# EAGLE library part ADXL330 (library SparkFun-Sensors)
Triple Axis Accelerometer Analog Devices ADXL330 +/-3g 2.4V-5.25V Analog output. Spark Fun Electronics SKU : COM-00730. Center pad paste layer has been reduced to avoid shorting.

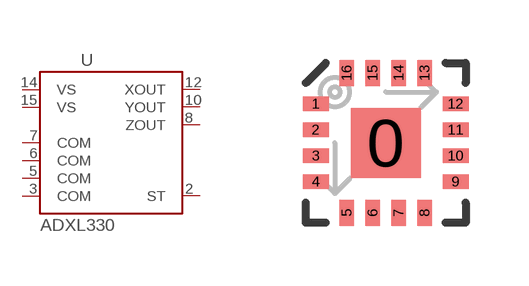
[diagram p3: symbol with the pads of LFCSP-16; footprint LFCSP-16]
Designator prefix -

## ADXL330SMD  [LFCSP-16]
2  ST
3  COM
5  COM
6  COM
7  COM
8  ZOUT
10  YOUT
12  XOUT
14  VS
15  VS

## Footprint LFCSP-16 (pad centres in mm)
smd 1.75 x 1.75: 0 0,0
smd 0.65 x 0.37: 1 -1.75,0.975; 2 -1.75,0.325; 3 -1.75,-0.325; 4 -1.75,-0.975; 9 1.75,-0.975; 10 1.75,-0.325; 11 1.75,0.325; 12 1.75,0.975
smd 0.37 x 0.65: 5 -0.975,-1.75; 6 -0.325,-1.75; 7 0.325,-1.75; 8 0.975,-1.75; 13 0.975,1.75; 14 0.325,1.75; 15 -0.325,1.75; 16 -0.975,1.75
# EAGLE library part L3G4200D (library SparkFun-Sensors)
L3G4200D Three-axis, digital output gyroscope The L3G4200D is a low-power three-axis angular rate sensor, has a full scale of ±250/±500/±2000 dps and is capable of measuring rates with a user-selectable bandwidth. It includes a sensing element and an IC interface capable of providing the measured angular rate to the external world through a digital interface (I2C/SPI). Package: 4x4x1.1 LGA-16 (LGA16-4x4.PAC)

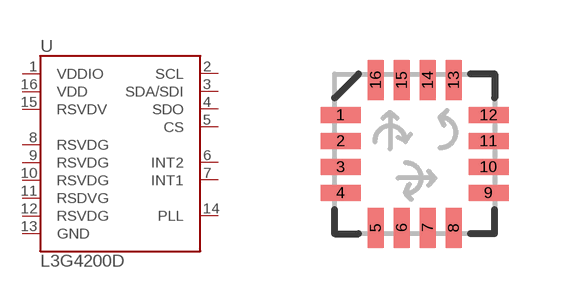
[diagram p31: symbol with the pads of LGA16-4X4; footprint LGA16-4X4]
Designator prefix U

## L3G4200D  [LGA16-4X4]
1  VDDIO
2  SCL
3  SDA/SDI
4  SDO
5  CS
6  INT2
7  INT1
8  RSVDG
9  RSVDG
10  RSVDG
11  RSDVG
12  RSVDG
13  GND
14  PLL
15  RSVDV
16  VDD

## Footprint LGA16-4X4 (pad centres in mm)
16-pin LGA Package 4x4x1.1mm 0.65mm pitch 4pins-by-4pins Package used by L3G4200D 3-axis gyro ***UNPROVEN***
smd 1 x 0.4: 1 -1.85,0.975; 2 -1.85,0.325; 3 -1.85,-0.325; 4 -1.85,-0.975; 9 1.85,-0.975; 10 1.85,-0.325; 11 1.85,0.325; 12 1.85,0.975
smd 0.4 x 1: 5 -0.975,-1.85; 6 -0.325,-1.85; 7 0.325,-1.85; 8 0.975,-1.85; 13 0.975,1.85; 14 0.325,1.85; 15 -0.325,1.85; 16 -0.975,1.85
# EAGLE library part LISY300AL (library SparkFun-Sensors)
Single-axis 300 deg/s analog gyroscope. Untested part.

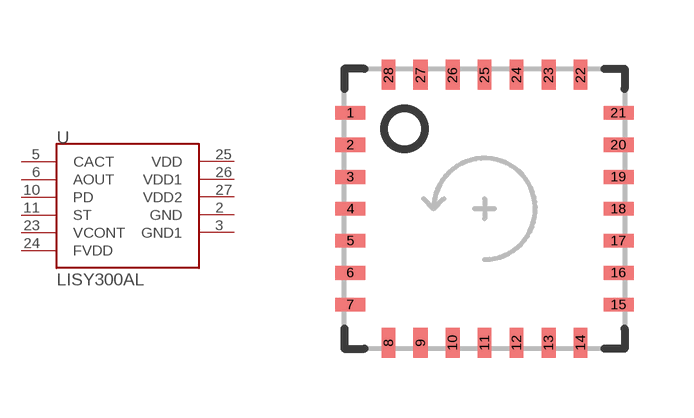
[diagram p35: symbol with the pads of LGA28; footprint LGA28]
Designator prefix -

## LISY300ALSMD  [LGA28]
2  GND
3  GND1
5  CACT
6  AOUT
10  PD
11  ST
23  VCONT
24  FVDD
25  VDD
26  VDD1
27  VDD2

## Footprint LGA28 (pad centres in mm)
Untested fp for LGA28 package
smd 0.75 x 0.35: 1 -3.35,2.4; 2 -3.35,1.6; 3 -3.35,0.8; 4 -3.35,0; 5 -3.35,-0.8; 6 -3.35,-1.6; 7 -3.35,-2.4; 15 3.35,-2.4; 16 3.35,-1.6; 17 3.35,-0.8; 18 3.35,0; 19 3.35,0.8; 20 3.35,1.6; 21 3.35,2.4
smd 0.35 x 0.75: 8 -2.4,-3.35; 9 -1.6,-3.35; 10 -0.8,-3.35; 11 0,-3.35; 12 0.8,-3.35; 13 1.6,-3.35; 14 2.4,-3.35; 22 2.4,3.35; 23 1.6,3.35; 24 0.8,3.35; 25 0,3.35; 26 -0.8,3.35; 27 -1.6,3.35; 28 -2.4,3.35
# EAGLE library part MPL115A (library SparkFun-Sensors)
MPL115A1 (SPI) and MPL115A2 (I2C) Miniature Digital Barometer 5.0x3.0x1.2mm LGA Package

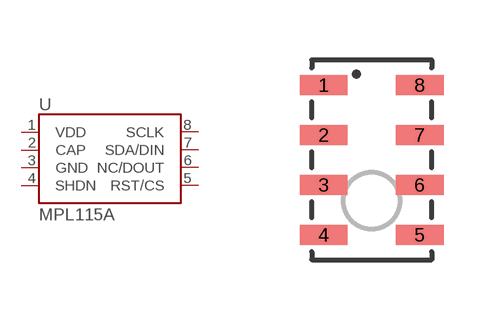
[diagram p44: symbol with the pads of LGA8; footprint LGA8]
Designator prefix U

## MPL115A  [LGA8]
1  VDD
2  CAP
3  GND
4  SHDN
5  RST/CS
6  NC/DOUT
7  SDA/DIN
8  SCLK

## Footprint LGA8 (pad centres in mm)
LGA8 Package **UNPROVEN** 5.0x3.0x1.2mm 8-pad Used in MPL115A1 -
smd 1.2 x 0.5: 1 -1.2,1.875; 2 -1.2,0.625; 3 -1.2,-0.625; 4 -1.2,-1.875; 5 1.2,-1.875; 6 1.2,-0.625; 7 1.2,0.625; 8 1.2,1.875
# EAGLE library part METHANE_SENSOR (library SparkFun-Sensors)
MQ-4 Methane Gas Sensor SEN-09404

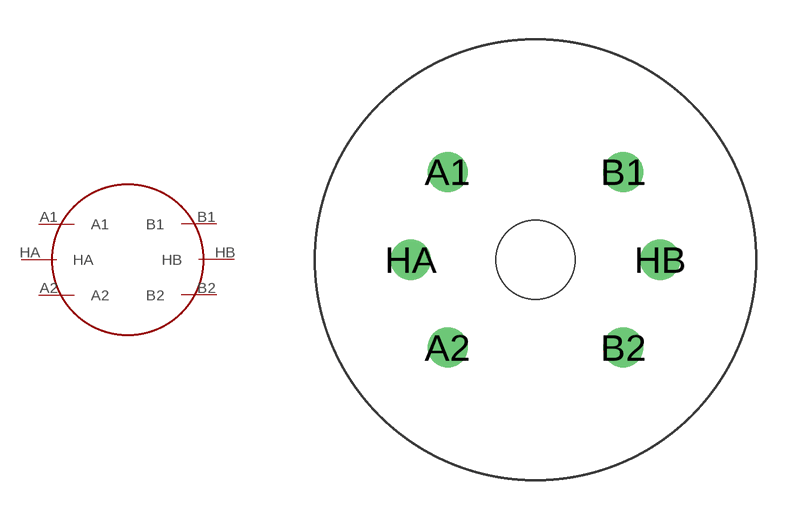
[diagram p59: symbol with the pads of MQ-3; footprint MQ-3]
Designator prefix -

## METHANE_SENSOR  [MQ-3]
A1  A1
A2  A2
B1  B1
B2  B2
HA  HA
HB  HB

## Footprint MQ-3 (pad centres in mm)
MQ-3 in Configuration B
drill 1.016: A1 -3.35,3.35; A2 -3.35,-3.35; B1 3.35,3.35; B2 3.35,-3.35; HA -4.75,0; HB 4.75,0
hole 3 at 0,0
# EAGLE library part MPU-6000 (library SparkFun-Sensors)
MPU-6000 - I2C address is 0x68 with AD0 low and 0x69 with AD0 high.

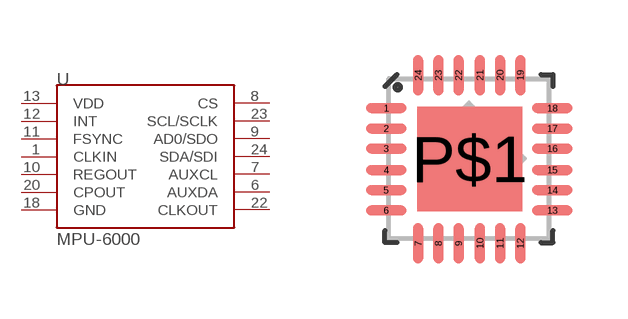
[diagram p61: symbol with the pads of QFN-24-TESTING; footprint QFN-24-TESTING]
Designator prefix U

## MPU-6000QFN-24  [QFN-24-TESTING]
1  CLKIN
6  AUXDA
7  AUXCL
8  CS
9  AD0/SDO
10  REGOUT
11  FSYNC
12  INT
13  VDD
18  GND
20  CPOUT
22  CLKOUT
23  SCL/SCLK
24  SDA/SDI

## Footprint QFN-24-TESTING (pad centres in mm)
This is the testing package I pulled from the MPU-6050 breakout board. This package is tested and works.
smd 1.016 x 0.254: 1 -2.066,1.257; 2 -2.066,0.75; 3 -2.066,0.247; 4 -2.066,-0.287; 5 -2.066,-0.792; 6 -2.066,-1.297; 13 2.086,-1.297; 14 2.086,-0.792; 15 2.086,-0.287; 16 2.086,0.247; 17 2.086,0.75; 18 2.086,1.257
smd 0.254 x 1.016: 7 -1.267,-2.122; 8 -0.762,-2.122; 9 -0.258,-2.122; 10 0.278,-2.122; 11 0.78,-2.122; 12 1.287,-2.122; 19 1.287,2.082; 20 0.78,2.082; 21 0.278,2.082; 22 -0.258,2.082; 23 -0.762,2.082; 24 -1.267,2.082
smd 2.616 x 2.616: P$1 0.02,-0.01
